VERSION 5.8 ;
UNITS
  DATABASE MICRONS 2000 ;
END UNITS
SITE core7
  CLASS CORE ;
  SIZE 0.054 BY 0.27 ;
END core7
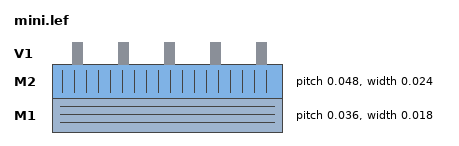
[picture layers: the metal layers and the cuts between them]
LAYER M1
  TYPE ROUTING ;
  DIRECTION HORIZONTAL ;
  PITCH 0.036 ;
  WIDTH 0.018 ;
  RESISTANCE RPERSQ 38.0 ;
  CAPACITANCE CPERSQDIST 0.0002 ;
  EDGECAPACITANCE 0.00005 ;
END M1
LAYER M2
  TYPE ROUTING ;
  DIRECTION VERTICAL ;
  PITCH 0.048 ;
  WIDTH 0.024 ;
END M2
LAYER V1
  TYPE CUT ;
END V1
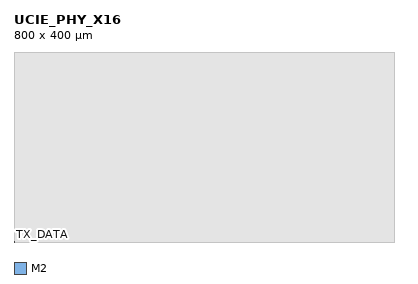
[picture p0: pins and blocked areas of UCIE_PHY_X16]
MACRO UCIE_PHY_X16
  CLASS BLOCK ;
  ORIGIN 0 0 ;
  SIZE 800.0 BY 400.0 ;
  PIN TX_DATA
    DIRECTION INPUT ;
    USE SIGNAL ;
    PORT
      LAYER M2 ;
        RECT 0 0 1 1 ;
    END
  END TX_DATA
  PIN RX_DATA
    DIRECTION OUTPUT ;
    USE SIGNAL ;
  END RX_DATA
  PIN VDD
    DIRECTION INOUT ;
    USE POWER ;
  END VDD
  OBS
    LAYER M1 ;
      RECT 0 0 800 400 ;
  END
END UCIE_PHY_X16
END LIBRARY
